VERSION 5.7 ;
  NOWIREEXTENSIONATPIN ON ;
  DIVIDERCHAR "/" ;
  BUSBITCHARS "[]" ;
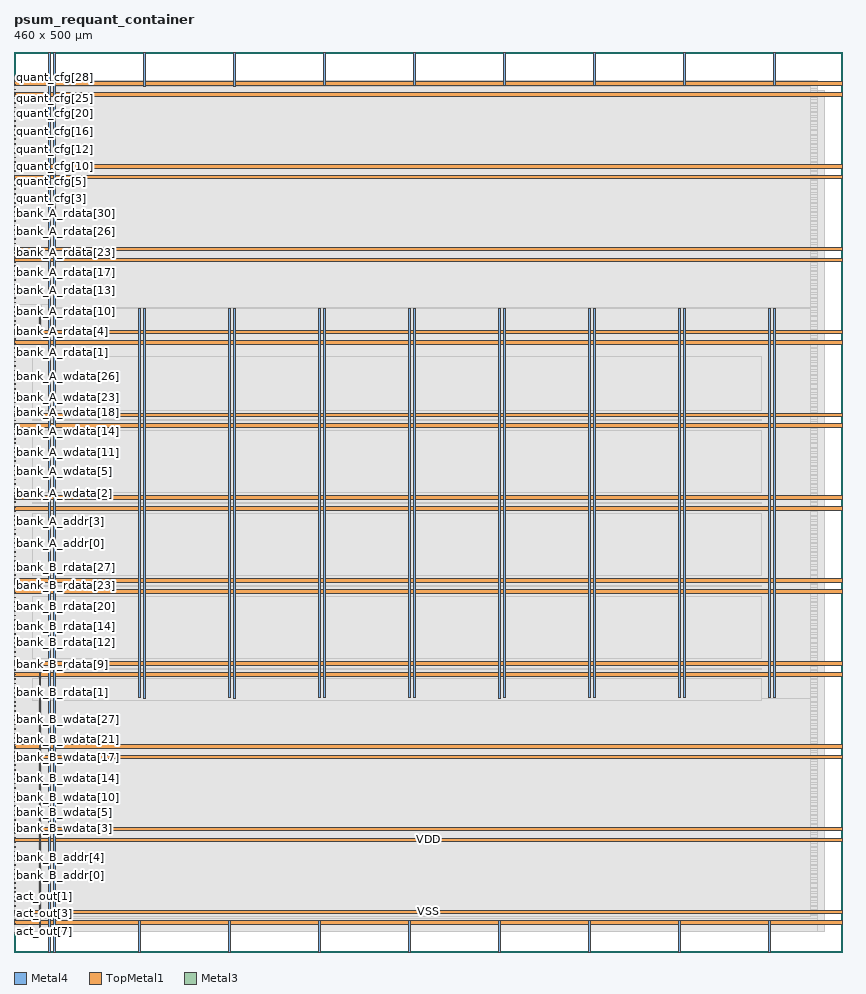
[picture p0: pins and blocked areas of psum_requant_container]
MACRO psum_requant_container
  CLASS BLOCK ;
  FOREIGN psum_requant_container ;
  ORIGIN 0.000 0.000 ;
  SIZE 460.000 BY 500.000 ;
  PIN VDD
    DIRECTION INOUT ;
    USE POWER ;
    PORT
      LAYER Metal4 ;
        RECT 19.100 0.000 20.100 500.000 ;
    END
    PORT
      LAYER Metal4 ;
        RECT 69.100 0.000 70.100 17.520 ;
    END
    PORT
      LAYER Metal4 ;
        RECT 69.100 141.260 70.100 357.520 ;
    END
    PORT
      LAYER Metal4 ;
        RECT 119.100 0.000 120.100 17.520 ;
    END
    PORT
      LAYER Metal4 ;
        RECT 119.100 141.260 120.100 357.520 ;
    END
    PORT
      LAYER Metal4 ;
        RECT 169.100 0.000 170.100 17.520 ;
    END
    PORT
      LAYER Metal4 ;
        RECT 169.100 141.260 170.100 357.520 ;
    END
    PORT
      LAYER Metal4 ;
        RECT 219.100 0.000 220.100 17.520 ;
    END
    PORT
      LAYER Metal4 ;
        RECT 219.100 141.260 220.100 357.520 ;
    END
    PORT
      LAYER Metal4 ;
        RECT 269.100 0.000 270.100 17.760 ;
    END
    PORT
      LAYER Metal4 ;
        RECT 269.100 141.020 270.100 357.760 ;
    END
    PORT
      LAYER Metal4 ;
        RECT 319.100 0.000 320.100 17.520 ;
    END
    PORT
      LAYER Metal4 ;
        RECT 319.100 141.260 320.100 357.520 ;
    END
    PORT
      LAYER Metal4 ;
        RECT 369.100 0.000 370.100 17.520 ;
    END
    PORT
      LAYER Metal4 ;
        RECT 369.100 141.260 370.100 357.520 ;
    END
    PORT
      LAYER Metal4 ;
        RECT 419.100 0.000 420.100 17.520 ;
    END
    PORT
      LAYER Metal4 ;
        RECT 419.100 141.260 420.100 357.520 ;
    END
    PORT
      LAYER TopMetal1 ;
        RECT 0.000 15.240 460.000 17.240 ;
    END
    PORT
      LAYER TopMetal1 ;
        RECT 0.000 61.270 460.000 63.270 ;
    END
    PORT
      LAYER TopMetal1 ;
        RECT 0.000 107.300 460.000 109.300 ;
    END
    PORT
      LAYER TopMetal1 ;
        RECT 0.000 153.330 460.000 155.330 ;
    END
    PORT
      LAYER TopMetal1 ;
        RECT 0.000 199.360 460.000 201.360 ;
    END
    PORT
      LAYER TopMetal1 ;
        RECT 0.000 245.390 460.000 247.390 ;
    END
    PORT
      LAYER TopMetal1 ;
        RECT 0.000 291.420 460.000 293.420 ;
    END
    PORT
      LAYER TopMetal1 ;
        RECT 0.000 337.450 460.000 339.450 ;
    END
    PORT
      LAYER TopMetal1 ;
        RECT 0.000 383.480 460.000 385.480 ;
    END
    PORT
      LAYER TopMetal1 ;
        RECT 0.000 429.510 460.000 431.510 ;
    END
    PORT
      LAYER TopMetal1 ;
        RECT 0.000 475.540 460.000 477.540 ;
    END
  END VDD
  PIN VSS
    DIRECTION INOUT ;
    USE GROUND ;
    PORT
      LAYER Metal4 ;
        RECT 22.100 0.000 23.100 500.000 ;
    END
    PORT
      LAYER Metal4 ;
        RECT 72.100 141.020 73.100 357.760 ;
    END
    PORT
      LAYER Metal4 ;
        RECT 72.100 481.020 73.100 500.000 ;
    END
    PORT
      LAYER Metal4 ;
        RECT 122.100 141.020 123.100 357.760 ;
    END
    PORT
      LAYER Metal4 ;
        RECT 122.100 481.020 123.100 500.000 ;
    END
    PORT
      LAYER Metal4 ;
        RECT 172.100 141.260 173.100 357.520 ;
    END
    PORT
      LAYER Metal4 ;
        RECT 172.100 481.260 173.100 500.000 ;
    END
    PORT
      LAYER Metal4 ;
        RECT 222.100 141.260 223.100 357.520 ;
    END
    PORT
      LAYER Metal4 ;
        RECT 222.100 481.260 223.100 500.000 ;
    END
    PORT
      LAYER Metal4 ;
        RECT 272.100 141.260 273.100 357.520 ;
    END
    PORT
      LAYER Metal4 ;
        RECT 272.100 481.260 273.100 500.000 ;
    END
    PORT
      LAYER Metal4 ;
        RECT 322.100 141.260 323.100 357.520 ;
    END
    PORT
      LAYER Metal4 ;
        RECT 322.100 481.260 323.100 500.000 ;
    END
    PORT
      LAYER Metal4 ;
        RECT 372.100 141.260 373.100 357.520 ;
    END
    PORT
      LAYER Metal4 ;
        RECT 372.100 481.260 373.100 500.000 ;
    END
    PORT
      LAYER Metal4 ;
        RECT 422.100 141.260 423.100 357.520 ;
    END
    PORT
      LAYER Metal4 ;
        RECT 422.100 481.260 423.100 500.000 ;
    END
    PORT
      LAYER TopMetal1 ;
        RECT 0.000 21.240 460.000 23.240 ;
    END
    PORT
      LAYER TopMetal1 ;
        RECT 0.000 67.270 460.000 69.270 ;
    END
    PORT
      LAYER TopMetal1 ;
        RECT 0.000 113.300 460.000 115.300 ;
    END
    PORT
      LAYER TopMetal1 ;
        RECT 0.000 159.330 460.000 161.330 ;
    END
    PORT
      LAYER TopMetal1 ;
        RECT 0.000 205.360 460.000 207.360 ;
    END
    PORT
      LAYER TopMetal1 ;
        RECT 0.000 251.390 460.000 253.390 ;
    END
    PORT
      LAYER TopMetal1 ;
        RECT 0.000 297.420 460.000 299.420 ;
    END
    PORT
      LAYER TopMetal1 ;
        RECT 0.000 343.450 460.000 345.450 ;
    END
    PORT
      LAYER TopMetal1 ;
        RECT 0.000 389.480 460.000 391.480 ;
    END
    PORT
      LAYER TopMetal1 ;
        RECT 0.000 435.510 460.000 437.510 ;
    END
    PORT
      LAYER TopMetal1 ;
        RECT 0.000 481.540 460.000 483.540 ;
    END
    PORT
      LAYER Metal4 ;
        RECT 13.900 11.120 14.900 155.200 ;
    END
    PORT
      LAYER Metal4 ;
        RECT 13.900 343.760 14.900 359.320 ;
    END
  END VSS
  PIN act_out[0]
    DIRECTION OUTPUT ;
    USE SIGNAL ;
    ANTENNADIFFAREA 0.708600 ;
    PORT
      LAYER Metal3 ;
        RECT 0.000 32.980 1.000 33.380 ;
    END
  END act_out[0]
  PIN act_out[1]
    DIRECTION OUTPUT ;
    USE SIGNAL ;
    ANTENNADIFFAREA 0.708600 ;
    PORT
      LAYER Metal3 ;
        RECT 0.000 30.460 1.000 30.860 ;
    END
  END act_out[1]
  PIN act_out[2]
    DIRECTION OUTPUT ;
    USE SIGNAL ;
    ANTENNADIFFAREA 0.708600 ;
    PORT
      LAYER Metal3 ;
        RECT 0.000 27.940 1.000 28.340 ;
    END
  END act_out[2]
  PIN act_out[3]
    DIRECTION OUTPUT ;
    USE SIGNAL ;
    ANTENNADIFFAREA 0.708600 ;
    PORT
      LAYER Metal3 ;
        RECT 0.000 25.420 1.000 25.820 ;
    END
  END act_out[3]
  PIN act_out[4]
    DIRECTION OUTPUT ;
    USE SIGNAL ;
    ANTENNADIFFAREA 0.708600 ;
    PORT
      LAYER Metal3 ;
        RECT 0.000 22.900 1.000 23.300 ;
    END
  END act_out[4]
  PIN act_out[5]
    DIRECTION OUTPUT ;
    USE SIGNAL ;
    ANTENNADIFFAREA 0.708600 ;
    PORT
      LAYER Metal3 ;
        RECT 0.000 20.380 1.000 20.780 ;
    END
  END act_out[5]
  PIN act_out[6]
    DIRECTION OUTPUT ;
    USE SIGNAL ;
    ANTENNADIFFAREA 0.708600 ;
    PORT
      LAYER Metal3 ;
        RECT 0.000 17.860 1.000 18.260 ;
    END
  END act_out[6]
  PIN act_out[7]
    DIRECTION OUTPUT ;
    USE SIGNAL ;
    ANTENNADIFFAREA 0.708600 ;
    PORT
      LAYER Metal3 ;
        RECT 0.000 15.340 1.000 15.740 ;
    END
  END act_out[7]
  PIN bank_A_addr[0]
    DIRECTION INPUT ;
    USE SIGNAL ;
    ANTENNAGATEAREA 0.180700 ;
    PORT
      LAYER Metal3 ;
        RECT 0.000 227.020 1.000 227.420 ;
    END
  END bank_A_addr[0]
  PIN bank_A_addr[1]
    DIRECTION INPUT ;
    USE SIGNAL ;
    ANTENNAGATEAREA 0.180700 ;
    PORT
      LAYER Metal3 ;
        RECT 0.000 229.540 1.000 229.940 ;
    END
  END bank_A_addr[1]
  PIN bank_A_addr[2]
    DIRECTION INPUT ;
    USE SIGNAL ;
    ANTENNAGATEAREA 0.180700 ;
    PORT
      LAYER Metal3 ;
        RECT 0.000 232.060 1.000 232.460 ;
    END
  END bank_A_addr[2]
  PIN bank_A_addr[3]
    DIRECTION INPUT ;
    USE SIGNAL ;
    ANTENNAGATEAREA 0.180700 ;
    PORT
      LAYER Metal3 ;
        RECT 0.000 234.580 1.000 234.980 ;
    END
  END bank_A_addr[3]
  PIN bank_A_addr[4]
    DIRECTION INPUT ;
    USE SIGNAL ;
    ANTENNAGATEAREA 0.180700 ;
    PORT
      LAYER Metal3 ;
        RECT 0.000 237.100 1.000 237.500 ;
    END
  END bank_A_addr[4]
  PIN bank_A_addr[5]
    DIRECTION INPUT ;
    USE SIGNAL ;
    ANTENNAGATEAREA 0.180700 ;
    PORT
      LAYER Metal3 ;
        RECT 0.000 239.620 1.000 240.020 ;
    END
  END bank_A_addr[5]
  PIN bank_A_addr[6]
    DIRECTION INPUT ;
    USE SIGNAL ;
    ANTENNAGATEAREA 0.180700 ;
    PORT
      LAYER Metal3 ;
        RECT 0.000 242.140 1.000 242.540 ;
    END
  END bank_A_addr[6]
  PIN bank_A_addr[7]
    DIRECTION INPUT ;
    USE SIGNAL ;
    ANTENNAGATEAREA 0.180700 ;
    PORT
      LAYER Metal3 ;
        RECT 0.000 244.660 1.000 245.060 ;
    END
  END bank_A_addr[7]
  PIN bank_A_rdata[0]
    DIRECTION OUTPUT ;
    USE SIGNAL ;
    ANTENNADIFFAREA 0.708600 ;
    PORT
      LAYER Metal3 ;
        RECT 0.000 330.340 1.000 330.740 ;
    END
  END bank_A_rdata[0]
  PIN bank_A_rdata[10]
    DIRECTION OUTPUT ;
    USE SIGNAL ;
    ANTENNADIFFAREA 0.708600 ;
    PORT
      LAYER Metal3 ;
        RECT 0.000 355.540 1.000 355.940 ;
    END
  END bank_A_rdata[10]
  PIN bank_A_rdata[11]
    DIRECTION OUTPUT ;
    USE SIGNAL ;
    ANTENNADIFFAREA 0.708600 ;
    PORT
      LAYER Metal3 ;
        RECT 0.000 358.060 1.000 358.460 ;
    END
  END bank_A_rdata[11]
  PIN bank_A_rdata[12]
    DIRECTION OUTPUT ;
    USE SIGNAL ;
    ANTENNADIFFAREA 0.708600 ;
    PORT
      LAYER Metal3 ;
        RECT 0.000 360.580 1.000 360.980 ;
    END
  END bank_A_rdata[12]
  PIN bank_A_rdata[13]
    DIRECTION OUTPUT ;
    USE SIGNAL ;
    ANTENNADIFFAREA 0.708600 ;
    PORT
      LAYER Metal3 ;
        RECT 0.000 363.100 1.000 363.500 ;
    END
  END bank_A_rdata[13]
  PIN bank_A_rdata[14]
    DIRECTION OUTPUT ;
    USE SIGNAL ;
    ANTENNADIFFAREA 0.708600 ;
    PORT
      LAYER Metal3 ;
        RECT 0.000 365.620 1.000 366.020 ;
    END
  END bank_A_rdata[14]
  PIN bank_A_rdata[15]
    DIRECTION OUTPUT ;
    USE SIGNAL ;
    ANTENNADIFFAREA 0.708600 ;
    PORT
      LAYER Metal3 ;
        RECT 0.000 368.140 1.000 368.540 ;
    END
  END bank_A_rdata[15]
  PIN bank_A_rdata[16]
    DIRECTION OUTPUT ;
    USE SIGNAL ;
    ANTENNADIFFAREA 0.708600 ;
    PORT
      LAYER Metal3 ;
        RECT 0.000 370.660 1.000 371.060 ;
    END
  END bank_A_rdata[16]
  PIN bank_A_rdata[17]
    DIRECTION OUTPUT ;
    USE SIGNAL ;
    ANTENNADIFFAREA 0.708600 ;
    PORT
      LAYER Metal3 ;
        RECT 0.000 373.180 1.000 373.580 ;
    END
  END bank_A_rdata[17]
  PIN bank_A_rdata[18]
    DIRECTION OUTPUT ;
    USE SIGNAL ;
    ANTENNADIFFAREA 0.708600 ;
    PORT
      LAYER Metal3 ;
        RECT 0.000 375.700 1.000 376.100 ;
    END
  END bank_A_rdata[18]
  PIN bank_A_rdata[19]
    DIRECTION OUTPUT ;
    USE SIGNAL ;
    ANTENNADIFFAREA 0.708600 ;
    PORT
      LAYER Metal3 ;
        RECT 0.000 378.220 1.000 378.620 ;
    END
  END bank_A_rdata[19]
  PIN bank_A_rdata[1]
    DIRECTION OUTPUT ;
    USE SIGNAL ;
    ANTENNADIFFAREA 0.708600 ;
    PORT
      LAYER Metal3 ;
        RECT 0.000 332.860 1.000 333.260 ;
    END
  END bank_A_rdata[1]
  PIN bank_A_rdata[20]
    DIRECTION OUTPUT ;
    USE SIGNAL ;
    ANTENNADIFFAREA 0.708600 ;
    PORT
      LAYER Metal3 ;
        RECT 0.000 380.740 1.000 381.140 ;
    END
  END bank_A_rdata[20]
  PIN bank_A_rdata[21]
    DIRECTION OUTPUT ;
    USE SIGNAL ;
    ANTENNADIFFAREA 0.708600 ;
    PORT
      LAYER Metal3 ;
        RECT 0.000 383.260 1.000 383.660 ;
    END
  END bank_A_rdata[21]
  PIN bank_A_rdata[22]
    DIRECTION OUTPUT ;
    USE SIGNAL ;
    ANTENNADIFFAREA 0.708600 ;
    PORT
      LAYER Metal3 ;
        RECT 0.000 385.780 1.000 386.180 ;
    END
  END bank_A_rdata[22]
  PIN bank_A_rdata[23]
    DIRECTION OUTPUT ;
    USE SIGNAL ;
    ANTENNADIFFAREA 0.708600 ;
    PORT
      LAYER Metal3 ;
        RECT 0.000 388.300 1.000 388.700 ;
    END
  END bank_A_rdata[23]
  PIN bank_A_rdata[24]
    DIRECTION OUTPUT ;
    USE SIGNAL ;
    ANTENNADIFFAREA 0.708600 ;
    PORT
      LAYER Metal3 ;
        RECT 0.000 390.820 1.000 391.220 ;
    END
  END bank_A_rdata[24]
  PIN bank_A_rdata[25]
    DIRECTION OUTPUT ;
    USE SIGNAL ;
    ANTENNADIFFAREA 0.708600 ;
    PORT
      LAYER Metal3 ;
        RECT 0.000 393.340 1.000 393.740 ;
    END
  END bank_A_rdata[25]
  PIN bank_A_rdata[26]
    DIRECTION OUTPUT ;
    USE SIGNAL ;
    ANTENNADIFFAREA 0.708600 ;
    PORT
      LAYER Metal3 ;
        RECT 0.000 395.860 1.000 396.260 ;
    END
  END bank_A_rdata[26]
  PIN bank_A_rdata[27]
    DIRECTION OUTPUT ;
    USE SIGNAL ;
    ANTENNADIFFAREA 0.708600 ;
    PORT
      LAYER Metal3 ;
        RECT 0.000 398.380 1.000 398.780 ;
    END
  END bank_A_rdata[27]
  PIN bank_A_rdata[28]
    DIRECTION OUTPUT ;
    USE SIGNAL ;
    ANTENNADIFFAREA 0.708600 ;
    PORT
      LAYER Metal3 ;
        RECT 0.000 400.900 1.000 401.300 ;
    END
  END bank_A_rdata[28]
  PIN bank_A_rdata[29]
    DIRECTION OUTPUT ;
    USE SIGNAL ;
    ANTENNADIFFAREA 0.708600 ;
    PORT
      LAYER Metal3 ;
        RECT 0.000 403.420 1.000 403.820 ;
    END
  END bank_A_rdata[29]
  PIN bank_A_rdata[2]
    DIRECTION OUTPUT ;
    USE SIGNAL ;
    ANTENNADIFFAREA 0.708600 ;
    PORT
      LAYER Metal3 ;
        RECT 0.000 335.380 1.000 335.780 ;
    END
  END bank_A_rdata[2]
  PIN bank_A_rdata[30]
    DIRECTION OUTPUT ;
    USE SIGNAL ;
    ANTENNADIFFAREA 0.708600 ;
    PORT
      LAYER Metal3 ;
        RECT 0.000 405.940 1.000 406.340 ;
    END
  END bank_A_rdata[30]
  PIN bank_A_rdata[31]
    DIRECTION OUTPUT ;
    USE SIGNAL ;
    ANTENNADIFFAREA 0.708600 ;
    PORT
      LAYER Metal3 ;
        RECT 0.000 408.460 1.000 408.860 ;
    END
  END bank_A_rdata[31]
  PIN bank_A_rdata[3]
    DIRECTION OUTPUT ;
    USE SIGNAL ;
    ANTENNADIFFAREA 0.708600 ;
    PORT
      LAYER Metal3 ;
        RECT 0.000 337.900 1.000 338.300 ;
    END
  END bank_A_rdata[3]
  PIN bank_A_rdata[4]
    DIRECTION OUTPUT ;
    USE SIGNAL ;
    ANTENNADIFFAREA 0.708600 ;
    PORT
      LAYER Metal3 ;
        RECT 0.000 340.420 1.000 340.820 ;
    END
  END bank_A_rdata[4]
  PIN bank_A_rdata[5]
    DIRECTION OUTPUT ;
    USE SIGNAL ;
    ANTENNADIFFAREA 0.708600 ;
    PORT
      LAYER Metal3 ;
        RECT 0.000 342.940 1.000 343.340 ;
    END
  END bank_A_rdata[5]
  PIN bank_A_rdata[6]
    DIRECTION OUTPUT ;
    USE SIGNAL ;
    ANTENNADIFFAREA 0.708600 ;
    PORT
      LAYER Metal3 ;
        RECT 0.000 345.460 1.000 345.860 ;
    END
  END bank_A_rdata[6]
  PIN bank_A_rdata[7]
    DIRECTION OUTPUT ;
    USE SIGNAL ;
    ANTENNADIFFAREA 0.708600 ;
    PORT
      LAYER Metal3 ;
        RECT 0.000 347.980 1.000 348.380 ;
    END
  END bank_A_rdata[7]
  PIN bank_A_rdata[8]
    DIRECTION OUTPUT ;
    USE SIGNAL ;
    ANTENNADIFFAREA 0.708600 ;
    PORT
      LAYER Metal3 ;
        RECT 0.000 350.500 1.000 350.900 ;
    END
  END bank_A_rdata[8]
  PIN bank_A_rdata[9]
    DIRECTION OUTPUT ;
    USE SIGNAL ;
    ANTENNADIFFAREA 0.708600 ;
    PORT
      LAYER Metal3 ;
        RECT 0.000 353.020 1.000 353.420 ;
    END
  END bank_A_rdata[9]
  PIN bank_A_wdata[0]
    DIRECTION INPUT ;
    USE SIGNAL ;
    ANTENNAGATEAREA 0.180700 ;
    PORT
      LAYER Metal3 ;
        RECT 0.000 249.700 1.000 250.100 ;
    END
  END bank_A_wdata[0]
  PIN bank_A_wdata[10]
    DIRECTION INPUT ;
    USE SIGNAL ;
    ANTENNAGATEAREA 0.180700 ;
    PORT
      LAYER Metal3 ;
        RECT 0.000 274.900 1.000 275.300 ;
    END
  END bank_A_wdata[10]
  PIN bank_A_wdata[11]
    DIRECTION INPUT ;
    USE SIGNAL ;
    ANTENNAGATEAREA 0.180700 ;
    PORT
      LAYER Metal3 ;
        RECT 0.000 277.420 1.000 277.820 ;
    END
  END bank_A_wdata[11]
  PIN bank_A_wdata[12]
    DIRECTION INPUT ;
    USE SIGNAL ;
    ANTENNAGATEAREA 0.180700 ;
    PORT
      LAYER Metal3 ;
        RECT 0.000 279.940 1.000 280.340 ;
    END
  END bank_A_wdata[12]
  PIN bank_A_wdata[13]
    DIRECTION INPUT ;
    USE SIGNAL ;
    ANTENNAGATEAREA 0.180700 ;
    PORT
      LAYER Metal3 ;
        RECT 0.000 282.460 1.000 282.860 ;
    END
  END bank_A_wdata[13]
  PIN bank_A_wdata[14]
    DIRECTION INPUT ;
    USE SIGNAL ;
    ANTENNAGATEAREA 0.180700 ;
    PORT
      LAYER Metal3 ;
        RECT 0.000 284.980 1.000 285.380 ;
    END
  END bank_A_wdata[14]
  PIN bank_A_wdata[15]
    DIRECTION INPUT ;
    USE SIGNAL ;
    ANTENNAGATEAREA 0.180700 ;
    PORT
      LAYER Metal3 ;
        RECT 0.000 287.500 1.000 287.900 ;
    END
  END bank_A_wdata[15]
  PIN bank_A_wdata[16]
    DIRECTION INPUT ;
    USE SIGNAL ;
    ANTENNAGATEAREA 0.180700 ;
    PORT
      LAYER Metal3 ;
        RECT 0.000 290.020 1.000 290.420 ;
    END
  END bank_A_wdata[16]
  PIN bank_A_wdata[17]
    DIRECTION INPUT ;
    USE SIGNAL ;
    ANTENNAGATEAREA 0.180700 ;
    PORT
      LAYER Metal3 ;
        RECT 0.000 292.540 1.000 292.940 ;
    END
  END bank_A_wdata[17]
  PIN bank_A_wdata[18]
    DIRECTION INPUT ;
    USE SIGNAL ;
    ANTENNAGATEAREA 0.180700 ;
    PORT
      LAYER Metal3 ;
        RECT 0.000 295.060 1.000 295.460 ;
    END
  END bank_A_wdata[18]
  PIN bank_A_wdata[19]
    DIRECTION INPUT ;
    USE SIGNAL ;
    ANTENNAGATEAREA 0.180700 ;
    PORT
      LAYER Metal3 ;
        RECT 0.000 297.580 1.000 297.980 ;
    END
  END bank_A_wdata[19]
  PIN bank_A_wdata[1]
    DIRECTION INPUT ;
    USE SIGNAL ;
    ANTENNAGATEAREA 0.180700 ;
    PORT
      LAYER Metal3 ;
        RECT 0.000 252.220 1.000 252.620 ;
    END
  END bank_A_wdata[1]
  PIN bank_A_wdata[20]
    DIRECTION INPUT ;
    USE SIGNAL ;
    ANTENNAGATEAREA 0.180700 ;
    PORT
      LAYER Metal3 ;
        RECT 0.000 300.100 1.000 300.500 ;
    END
  END bank_A_wdata[20]
  PIN bank_A_wdata[21]
    DIRECTION INPUT ;
    USE SIGNAL ;
    ANTENNAGATEAREA 0.180700 ;
    PORT
      LAYER Metal3 ;
        RECT 0.000 302.620 1.000 303.020 ;
    END
  END bank_A_wdata[21]
  PIN bank_A_wdata[22]
    DIRECTION INPUT ;
    USE SIGNAL ;
    ANTENNAGATEAREA 0.180700 ;
    PORT
      LAYER Metal3 ;
        RECT 0.000 305.140 1.000 305.540 ;
    END
  END bank_A_wdata[22]
  PIN bank_A_wdata[23]
    DIRECTION INPUT ;
    USE SIGNAL ;
    ANTENNAGATEAREA 0.180700 ;
    PORT
      LAYER Metal3 ;
        RECT 0.000 307.660 1.000 308.060 ;
    END
  END bank_A_wdata[23]
  PIN bank_A_wdata[24]
    DIRECTION INPUT ;
    USE SIGNAL ;
    ANTENNAGATEAREA 0.180700 ;
    PORT
      LAYER Metal3 ;
        RECT 0.000 310.180 1.000 310.580 ;
    END
  END bank_A_wdata[24]
  PIN bank_A_wdata[25]
    DIRECTION INPUT ;
    USE SIGNAL ;
    ANTENNAGATEAREA 0.180700 ;
    PORT
      LAYER Metal3 ;
        RECT 0.000 312.700 1.000 313.100 ;
    END
  END bank_A_wdata[25]
  PIN bank_A_wdata[26]
    DIRECTION INPUT ;
    USE SIGNAL ;
    ANTENNAGATEAREA 0.180700 ;
    PORT
      LAYER Metal3 ;
        RECT 0.000 315.220 1.000 315.620 ;
    END
  END bank_A_wdata[26]
  PIN bank_A_wdata[27]
    DIRECTION INPUT ;
    USE SIGNAL ;
    ANTENNAGATEAREA 0.180700 ;
    PORT
      LAYER Metal3 ;
        RECT 0.000 317.740 1.000 318.140 ;
    END
  END bank_A_wdata[27]
  PIN bank_A_wdata[28]
    DIRECTION INPUT ;
    USE SIGNAL ;
    ANTENNAGATEAREA 0.180700 ;
    PORT
      LAYER Metal3 ;
        RECT 0.000 320.260 1.000 320.660 ;
    END
  END bank_A_wdata[28]
  PIN bank_A_wdata[29]
    DIRECTION INPUT ;
    USE SIGNAL ;
    ANTENNAGATEAREA 0.180700 ;
    PORT
      LAYER Metal3 ;
        RECT 0.000 322.780 1.000 323.180 ;
    END
  END bank_A_wdata[29]
  PIN bank_A_wdata[2]
    DIRECTION INPUT ;
    USE SIGNAL ;
    ANTENNAGATEAREA 0.180700 ;
    PORT
      LAYER Metal3 ;
        RECT 0.000 254.740 1.000 255.140 ;
    END
  END bank_A_wdata[2]
  PIN bank_A_wdata[30]
    DIRECTION INPUT ;
    USE SIGNAL ;
    ANTENNAGATEAREA 0.180700 ;
    PORT
      LAYER Metal3 ;
        RECT 0.000 325.300 1.000 325.700 ;
    END
  END bank_A_wdata[30]
  PIN bank_A_wdata[31]
    DIRECTION INPUT ;
    USE SIGNAL ;
    ANTENNAGATEAREA 0.180700 ;
    PORT
      LAYER Metal3 ;
        RECT 0.000 327.820 1.000 328.220 ;
    END
  END bank_A_wdata[31]
  PIN bank_A_wdata[3]
    DIRECTION INPUT ;
    USE SIGNAL ;
    ANTENNAGATEAREA 0.180700 ;
    PORT
      LAYER Metal3 ;
        RECT 0.000 257.260 1.000 257.660 ;
    END
  END bank_A_wdata[3]
  PIN bank_A_wdata[4]
    DIRECTION INPUT ;
    USE SIGNAL ;
    ANTENNAGATEAREA 0.180700 ;
    PORT
      LAYER Metal3 ;
        RECT 0.000 259.780 1.000 260.180 ;
    END
  END bank_A_wdata[4]
  PIN bank_A_wdata[5]
    DIRECTION INPUT ;
    USE SIGNAL ;
    ANTENNAGATEAREA 0.180700 ;
    PORT
      LAYER Metal3 ;
        RECT 0.000 262.300 1.000 262.700 ;
    END
  END bank_A_wdata[5]
  PIN bank_A_wdata[6]
    DIRECTION INPUT ;
    USE SIGNAL ;
    ANTENNAGATEAREA 0.180700 ;
    PORT
      LAYER Metal3 ;
        RECT 0.000 264.820 1.000 265.220 ;
    END
  END bank_A_wdata[6]
  PIN bank_A_wdata[7]
    DIRECTION INPUT ;
    USE SIGNAL ;
    ANTENNAGATEAREA 0.180700 ;
    PORT
      LAYER Metal3 ;
        RECT 0.000 267.340 1.000 267.740 ;
    END
  END bank_A_wdata[7]
  PIN bank_A_wdata[8]
    DIRECTION INPUT ;
    USE SIGNAL ;
    ANTENNAGATEAREA 0.180700 ;
    PORT
      LAYER Metal3 ;
        RECT 0.000 269.860 1.000 270.260 ;
    END
  END bank_A_wdata[8]
  PIN bank_A_wdata[9]
    DIRECTION INPUT ;
    USE SIGNAL ;
    ANTENNAGATEAREA 0.180700 ;
    PORT
      LAYER Metal3 ;
        RECT 0.000 272.380 1.000 272.780 ;
    END
  END bank_A_wdata[9]
  PIN bank_A_we
    DIRECTION INPUT ;
    USE SIGNAL ;
    ANTENNAGATEAREA 0.180700 ;
    PORT
      LAYER Metal3 ;
        RECT 0.000 247.180 1.000 247.580 ;
    END
  END bank_A_we
  PIN bank_B_addr[0]
    DIRECTION INPUT ;
    USE SIGNAL ;
    ANTENNAGATEAREA 0.180700 ;
    PORT
      LAYER Metal3 ;
        RECT 0.000 38.020 1.000 38.420 ;
    END
  END bank_B_addr[0]
  PIN bank_B_addr[1]
    DIRECTION INPUT ;
    USE SIGNAL ;
    ANTENNAGATEAREA 0.180700 ;
    PORT
      LAYER Metal3 ;
        RECT 0.000 40.540 1.000 40.940 ;
    END
  END bank_B_addr[1]
  PIN bank_B_addr[2]
    DIRECTION INPUT ;
    USE SIGNAL ;
    ANTENNAGATEAREA 0.180700 ;
    PORT
      LAYER Metal3 ;
        RECT 0.000 43.060 1.000 43.460 ;
    END
  END bank_B_addr[2]
  PIN bank_B_addr[3]
    DIRECTION INPUT ;
    USE SIGNAL ;
    ANTENNAGATEAREA 0.180700 ;
    PORT
      LAYER Metal3 ;
        RECT 0.000 45.580 1.000 45.980 ;
    END
  END bank_B_addr[3]
  PIN bank_B_addr[4]
    DIRECTION INPUT ;
    USE SIGNAL ;
    ANTENNAGATEAREA 0.180700 ;
    PORT
      LAYER Metal3 ;
        RECT 0.000 48.100 1.000 48.500 ;
    END
  END bank_B_addr[4]
  PIN bank_B_addr[5]
    DIRECTION INPUT ;
    USE SIGNAL ;
    ANTENNAGATEAREA 0.180700 ;
    PORT
      LAYER Metal3 ;
        RECT 0.000 50.620 1.000 51.020 ;
    END
  END bank_B_addr[5]
  PIN bank_B_addr[6]
    DIRECTION INPUT ;
    USE SIGNAL ;
    ANTENNAGATEAREA 0.180700 ;
    PORT
      LAYER Metal3 ;
        RECT 0.000 53.140 1.000 53.540 ;
    END
  END bank_B_addr[6]
  PIN bank_B_addr[7]
    DIRECTION INPUT ;
    USE SIGNAL ;
    ANTENNAGATEAREA 0.180700 ;
    PORT
      LAYER Metal3 ;
        RECT 0.000 55.660 1.000 56.060 ;
    END
  END bank_B_addr[7]
  PIN bank_B_rdata[0]
    DIRECTION OUTPUT ;
    USE SIGNAL ;
    ANTENNADIFFAREA 0.708600 ;
    PORT
      LAYER Metal3 ;
        RECT 0.000 141.340 1.000 141.740 ;
    END
  END bank_B_rdata[0]
  PIN bank_B_rdata[10]
    DIRECTION OUTPUT ;
    USE SIGNAL ;
    ANTENNADIFFAREA 0.708600 ;
    PORT
      LAYER Metal3 ;
        RECT 0.000 166.540 1.000 166.940 ;
    END
  END bank_B_rdata[10]
  PIN bank_B_rdata[11]
    DIRECTION OUTPUT ;
    USE SIGNAL ;
    ANTENNADIFFAREA 0.708600 ;
    PORT
      LAYER Metal3 ;
        RECT 0.000 169.060 1.000 169.460 ;
    END
  END bank_B_rdata[11]
  PIN bank_B_rdata[12]
    DIRECTION OUTPUT ;
    USE SIGNAL ;
    ANTENNADIFFAREA 0.708600 ;
    PORT
      LAYER Metal3 ;
        RECT 0.000 171.580 1.000 171.980 ;
    END
  END bank_B_rdata[12]
  PIN bank_B_rdata[13]
    DIRECTION OUTPUT ;
    USE SIGNAL ;
    ANTENNADIFFAREA 0.708600 ;
    PORT
      LAYER Metal3 ;
        RECT 0.000 174.100 1.000 174.500 ;
    END
  END bank_B_rdata[13]
  PIN bank_B_rdata[14]
    DIRECTION OUTPUT ;
    USE SIGNAL ;
    ANTENNADIFFAREA 0.708600 ;
    PORT
      LAYER Metal3 ;
        RECT 0.000 176.620 1.000 177.020 ;
    END
  END bank_B_rdata[14]
  PIN bank_B_rdata[15]
    DIRECTION OUTPUT ;
    USE SIGNAL ;
    ANTENNADIFFAREA 0.708600 ;
    PORT
      LAYER Metal3 ;
        RECT 0.000 179.140 1.000 179.540 ;
    END
  END bank_B_rdata[15]
  PIN bank_B_rdata[16]
    DIRECTION OUTPUT ;
    USE SIGNAL ;
    ANTENNADIFFAREA 0.708600 ;
    PORT
      LAYER Metal3 ;
        RECT 0.000 181.660 1.000 182.060 ;
    END
  END bank_B_rdata[16]
  PIN bank_B_rdata[17]
    DIRECTION OUTPUT ;
    USE SIGNAL ;
    ANTENNADIFFAREA 0.708600 ;
    PORT
      LAYER Metal3 ;
        RECT 0.000 184.180 1.000 184.580 ;
    END
  END bank_B_rdata[17]
  PIN bank_B_rdata[18]
    DIRECTION OUTPUT ;
    USE SIGNAL ;
    ANTENNADIFFAREA 0.708600 ;
    PORT
      LAYER Metal3 ;
        RECT 0.000 186.700 1.000 187.100 ;
    END
  END bank_B_rdata[18]
  PIN bank_B_rdata[19]
    DIRECTION OUTPUT ;
    USE SIGNAL ;
    ANTENNADIFFAREA 0.708600 ;
    PORT
      LAYER Metal3 ;
        RECT 0.000 189.220 1.000 189.620 ;
    END
  END bank_B_rdata[19]
  PIN bank_B_rdata[1]
    DIRECTION OUTPUT ;
    USE SIGNAL ;
    ANTENNADIFFAREA 0.708600 ;
    PORT
      LAYER Metal3 ;
        RECT 0.000 143.860 1.000 144.260 ;
    END
  END bank_B_rdata[1]
  PIN bank_B_rdata[20]
    DIRECTION OUTPUT ;
    USE SIGNAL ;
    ANTENNADIFFAREA 0.708600 ;
    PORT
      LAYER Metal3 ;
        RECT 0.000 191.740 1.000 192.140 ;
    END
  END bank_B_rdata[20]
  PIN bank_B_rdata[21]
    DIRECTION OUTPUT ;
    USE SIGNAL ;
    ANTENNADIFFAREA 0.708600 ;
    PORT
      LAYER Metal3 ;
        RECT 0.000 194.260 1.000 194.660 ;
    END
  END bank_B_rdata[21]
  PIN bank_B_rdata[22]
    DIRECTION OUTPUT ;
    USE SIGNAL ;
    ANTENNADIFFAREA 0.708600 ;
    PORT
      LAYER Metal3 ;
        RECT 0.000 196.780 1.000 197.180 ;
    END
  END bank_B_rdata[22]
  PIN bank_B_rdata[23]
    DIRECTION OUTPUT ;
    USE SIGNAL ;
    ANTENNADIFFAREA 0.708600 ;
    PORT
      LAYER Metal3 ;
        RECT 0.000 199.300 1.000 199.700 ;
    END
  END bank_B_rdata[23]
  PIN bank_B_rdata[24]
    DIRECTION OUTPUT ;
    USE SIGNAL ;
    ANTENNADIFFAREA 0.708600 ;
    PORT
      LAYER Metal3 ;
        RECT 0.000 201.820 1.000 202.220 ;
    END
  END bank_B_rdata[24]
  PIN bank_B_rdata[25]
    DIRECTION OUTPUT ;
    USE SIGNAL ;
    ANTENNADIFFAREA 0.708600 ;
    PORT
      LAYER Metal3 ;
        RECT 0.000 204.340 1.000 204.740 ;
    END
  END bank_B_rdata[25]
  PIN bank_B_rdata[26]
    DIRECTION OUTPUT ;
    USE SIGNAL ;
    ANTENNADIFFAREA 0.708600 ;
    PORT
      LAYER Metal3 ;
        RECT 0.000 206.860 1.000 207.260 ;
    END
  END bank_B_rdata[26]
  PIN bank_B_rdata[27]
    DIRECTION OUTPUT ;
    USE SIGNAL ;
    ANTENNADIFFAREA 0.708600 ;
    PORT
      LAYER Metal3 ;
        RECT 0.000 209.380 1.000 209.780 ;
    END
  END bank_B_rdata[27]
  PIN bank_B_rdata[28]
    DIRECTION OUTPUT ;
    USE SIGNAL ;
    ANTENNADIFFAREA 0.708600 ;
    PORT
      LAYER Metal3 ;
        RECT 0.000 211.900 1.000 212.300 ;
    END
  END bank_B_rdata[28]
  PIN bank_B_rdata[29]
    DIRECTION OUTPUT ;
    USE SIGNAL ;
    ANTENNADIFFAREA 0.708600 ;
    PORT
      LAYER Metal3 ;
        RECT 0.000 214.420 1.000 214.820 ;
    END
  END bank_B_rdata[29]
  PIN bank_B_rdata[2]
    DIRECTION OUTPUT ;
    USE SIGNAL ;
    ANTENNADIFFAREA 0.708600 ;
    PORT
      LAYER Metal3 ;
        RECT 0.000 146.380 1.000 146.780 ;
    END
  END bank_B_rdata[2]
  PIN bank_B_rdata[30]
    DIRECTION OUTPUT ;
    USE SIGNAL ;
    ANTENNADIFFAREA 0.708600 ;
    PORT
      LAYER Metal3 ;
        RECT 0.000 216.940 1.000 217.340 ;
    END
  END bank_B_rdata[30]
  PIN bank_B_rdata[31]
    DIRECTION OUTPUT ;
    USE SIGNAL ;
    ANTENNADIFFAREA 0.708600 ;
    PORT
      LAYER Metal3 ;
        RECT 0.000 219.460 1.000 219.860 ;
    END
  END bank_B_rdata[31]
  PIN bank_B_rdata[3]
    DIRECTION OUTPUT ;
    USE SIGNAL ;
    ANTENNADIFFAREA 0.708600 ;
    PORT
      LAYER Metal3 ;
        RECT 0.000 148.900 1.000 149.300 ;
    END
  END bank_B_rdata[3]
  PIN bank_B_rdata[4]
    DIRECTION OUTPUT ;
    USE SIGNAL ;
    ANTENNADIFFAREA 0.708600 ;
    PORT
      LAYER Metal3 ;
        RECT 0.000 151.420 1.000 151.820 ;
    END
  END bank_B_rdata[4]
  PIN bank_B_rdata[5]
    DIRECTION OUTPUT ;
    USE SIGNAL ;
    ANTENNADIFFAREA 0.708600 ;
    PORT
      LAYER Metal3 ;
        RECT 0.000 153.940 1.000 154.340 ;
    END
  END bank_B_rdata[5]
  PIN bank_B_rdata[6]
    DIRECTION OUTPUT ;
    USE SIGNAL ;
    ANTENNADIFFAREA 0.708600 ;
    PORT
      LAYER Metal3 ;
        RECT 0.000 156.460 1.000 156.860 ;
    END
  END bank_B_rdata[6]
  PIN bank_B_rdata[7]
    DIRECTION OUTPUT ;
    USE SIGNAL ;
    ANTENNADIFFAREA 0.708600 ;
    PORT
      LAYER Metal3 ;
        RECT 0.000 158.980 1.000 159.380 ;
    END
  END bank_B_rdata[7]
  PIN bank_B_rdata[8]
    DIRECTION OUTPUT ;
    USE SIGNAL ;
    ANTENNADIFFAREA 0.708600 ;
    PORT
      LAYER Metal3 ;
        RECT 0.000 161.500 1.000 161.900 ;
    END
  END bank_B_rdata[8]
  PIN bank_B_rdata[9]
    DIRECTION OUTPUT ;
    USE SIGNAL ;
    ANTENNADIFFAREA 0.708600 ;
    PORT
      LAYER Metal3 ;
        RECT 0.000 164.020 1.000 164.420 ;
    END
  END bank_B_rdata[9]
  PIN bank_B_wdata[0]
    DIRECTION INPUT ;
    USE SIGNAL ;
    ANTENNAGATEAREA 0.180700 ;
    PORT
      LAYER Metal3 ;
        RECT 0.000 60.700 1.000 61.100 ;
    END
  END bank_B_wdata[0]
  PIN bank_B_wdata[10]
    DIRECTION INPUT ;
    USE SIGNAL ;
    ANTENNAGATEAREA 0.180700 ;
    PORT
      LAYER Metal3 ;
        RECT 0.000 85.900 1.000 86.300 ;
    END
  END bank_B_wdata[10]
  PIN bank_B_wdata[11]
    DIRECTION INPUT ;
    USE SIGNAL ;
    ANTENNAGATEAREA 0.180700 ;
    PORT
      LAYER Metal3 ;
        RECT 0.000 88.420 1.000 88.820 ;
    END
  END bank_B_wdata[11]
  PIN bank_B_wdata[12]
    DIRECTION INPUT ;
    USE SIGNAL ;
    ANTENNAGATEAREA 0.180700 ;
    PORT
      LAYER Metal3 ;
        RECT 0.000 90.940 1.000 91.340 ;
    END
  END bank_B_wdata[12]
  PIN bank_B_wdata[13]
    DIRECTION INPUT ;
    USE SIGNAL ;
    ANTENNAGATEAREA 0.180700 ;
    PORT
      LAYER Metal3 ;
        RECT 0.000 93.460 1.000 93.860 ;
    END
  END bank_B_wdata[13]
  PIN bank_B_wdata[14]
    DIRECTION INPUT ;
    USE SIGNAL ;
    ANTENNAGATEAREA 0.180700 ;
    PORT
      LAYER Metal3 ;
        RECT 0.000 95.980 1.000 96.380 ;
    END
  END bank_B_wdata[14]
  PIN bank_B_wdata[15]
    DIRECTION INPUT ;
    USE SIGNAL ;
    ANTENNAGATEAREA 0.180700 ;
    PORT
      LAYER Metal3 ;
        RECT 0.000 98.500 1.000 98.900 ;
    END
  END bank_B_wdata[15]
  PIN bank_B_wdata[16]
    DIRECTION INPUT ;
    USE SIGNAL ;
    ANTENNAGATEAREA 0.180700 ;
    PORT
      LAYER Metal3 ;
        RECT 0.000 101.020 1.000 101.420 ;
    END
  END bank_B_wdata[16]
  PIN bank_B_wdata[17]
    DIRECTION INPUT ;
    USE SIGNAL ;
    ANTENNAGATEAREA 0.180700 ;
    PORT
      LAYER Metal3 ;
        RECT 0.000 103.540 1.000 103.940 ;
    END
  END bank_B_wdata[17]
  PIN bank_B_wdata[18]
    DIRECTION INPUT ;
    USE SIGNAL ;
    ANTENNAGATEAREA 0.180700 ;
    PORT
      LAYER Metal3 ;
        RECT 0.000 106.060 1.000 106.460 ;
    END
  END bank_B_wdata[18]
  PIN bank_B_wdata[19]
    DIRECTION INPUT ;
    USE SIGNAL ;
    ANTENNAGATEAREA 0.180700 ;
    PORT
      LAYER Metal3 ;
        RECT 0.000 108.580 1.000 108.980 ;
    END
  END bank_B_wdata[19]
  PIN bank_B_wdata[1]
    DIRECTION INPUT ;
    USE SIGNAL ;
    ANTENNAGATEAREA 0.180700 ;
    PORT
      LAYER Metal3 ;
        RECT 0.000 63.220 1.000 63.620 ;
    END
  END bank_B_wdata[1]
  PIN bank_B_wdata[20]
    DIRECTION INPUT ;
    USE SIGNAL ;
    ANTENNAGATEAREA 0.180700 ;
    PORT
      LAYER Metal3 ;
        RECT 0.000 111.100 1.000 111.500 ;
    END
  END bank_B_wdata[20]
  PIN bank_B_wdata[21]
    DIRECTION INPUT ;
    USE SIGNAL ;
    ANTENNAGATEAREA 0.180700 ;
    PORT
      LAYER Metal3 ;
        RECT 0.000 113.620 1.000 114.020 ;
    END
  END bank_B_wdata[21]
  PIN bank_B_wdata[22]
    DIRECTION INPUT ;
    USE SIGNAL ;
    ANTENNAGATEAREA 0.180700 ;
    PORT
      LAYER Metal3 ;
        RECT 0.000 116.140 1.000 116.540 ;
    END
  END bank_B_wdata[22]
  PIN bank_B_wdata[23]
    DIRECTION INPUT ;
    USE SIGNAL ;
    ANTENNAGATEAREA 0.180700 ;
    PORT
      LAYER Metal3 ;
        RECT 0.000 118.660 1.000 119.060 ;
    END
  END bank_B_wdata[23]
  PIN bank_B_wdata[24]
    DIRECTION INPUT ;
    USE SIGNAL ;
    ANTENNAGATEAREA 0.180700 ;
    PORT
      LAYER Metal3 ;
        RECT 0.000 121.180 1.000 121.580 ;
    END
  END bank_B_wdata[24]
  PIN bank_B_wdata[25]
    DIRECTION INPUT ;
    USE SIGNAL ;
    ANTENNAGATEAREA 0.180700 ;
    PORT
      LAYER Metal3 ;
        RECT 0.000 123.700 1.000 124.100 ;
    END
  END bank_B_wdata[25]
  PIN bank_B_wdata[26]
    DIRECTION INPUT ;
    USE SIGNAL ;
    ANTENNAGATEAREA 0.180700 ;
    PORT
      LAYER Metal3 ;
        RECT 0.000 126.220 1.000 126.620 ;
    END
  END bank_B_wdata[26]
  PIN bank_B_wdata[27]
    DIRECTION INPUT ;
    USE SIGNAL ;
    ANTENNAGATEAREA 0.180700 ;
    PORT
      LAYER Metal3 ;
        RECT 0.000 128.740 1.000 129.140 ;
    END
  END bank_B_wdata[27]
  PIN bank_B_wdata[28]
    DIRECTION INPUT ;
    USE SIGNAL ;
    ANTENNAGATEAREA 0.180700 ;
    PORT
      LAYER Metal3 ;
        RECT 0.000 131.260 1.000 131.660 ;
    END
  END bank_B_wdata[28]
  PIN bank_B_wdata[29]
    DIRECTION INPUT ;
    USE SIGNAL ;
    ANTENNAGATEAREA 0.180700 ;
    PORT
      LAYER Metal3 ;
        RECT 0.000 133.780 1.000 134.180 ;
    END
  END bank_B_wdata[29]
  PIN bank_B_wdata[2]
    DIRECTION INPUT ;
    USE SIGNAL ;
    ANTENNAGATEAREA 0.180700 ;
    PORT
      LAYER Metal3 ;
        RECT 0.000 65.740 1.000 66.140 ;
    END
  END bank_B_wdata[2]
  PIN bank_B_wdata[30]
    DIRECTION INPUT ;
    USE SIGNAL ;
    ANTENNAGATEAREA 0.180700 ;
    PORT
      LAYER Metal3 ;
        RECT 0.000 136.300 1.000 136.700 ;
    END
  END bank_B_wdata[30]
  PIN bank_B_wdata[31]
    DIRECTION INPUT ;
    USE SIGNAL ;
    ANTENNAGATEAREA 0.180700 ;
    PORT
      LAYER Metal3 ;
        RECT 0.000 138.820 1.000 139.220 ;
    END
  END bank_B_wdata[31]
  PIN bank_B_wdata[3]
    DIRECTION INPUT ;
    USE SIGNAL ;
    ANTENNAGATEAREA 0.180700 ;
    PORT
      LAYER Metal3 ;
        RECT 0.000 68.260 1.000 68.660 ;
    END
  END bank_B_wdata[3]
  PIN bank_B_wdata[4]
    DIRECTION INPUT ;
    USE SIGNAL ;
    ANTENNAGATEAREA 0.180700 ;
    PORT
      LAYER Metal3 ;
        RECT 0.000 70.780 1.000 71.180 ;
    END
  END bank_B_wdata[4]
  PIN bank_B_wdata[5]
    DIRECTION INPUT ;
    USE SIGNAL ;
    ANTENNAGATEAREA 0.180700 ;
    PORT
      LAYER Metal3 ;
        RECT 0.000 73.300 1.000 73.700 ;
    END
  END bank_B_wdata[5]
  PIN bank_B_wdata[6]
    DIRECTION INPUT ;
    USE SIGNAL ;
    ANTENNAGATEAREA 0.180700 ;
    PORT
      LAYER Metal3 ;
        RECT 0.000 75.820 1.000 76.220 ;
    END
  END bank_B_wdata[6]
  PIN bank_B_wdata[7]
    DIRECTION INPUT ;
    USE SIGNAL ;
    ANTENNAGATEAREA 0.180700 ;
    PORT
      LAYER Metal3 ;
        RECT 0.000 78.340 1.000 78.740 ;
    END
  END bank_B_wdata[7]
  PIN bank_B_wdata[8]
    DIRECTION INPUT ;
    USE SIGNAL ;
    ANTENNAGATEAREA 0.180700 ;
    PORT
      LAYER Metal3 ;
        RECT 0.000 80.860 1.000 81.260 ;
    END
  END bank_B_wdata[8]
  PIN bank_B_wdata[9]
    DIRECTION INPUT ;
    USE SIGNAL ;
    ANTENNAGATEAREA 0.180700 ;
    PORT
      LAYER Metal3 ;
        RECT 0.000 83.380 1.000 83.780 ;
    END
  END bank_B_wdata[9]
  PIN bank_B_we
    DIRECTION INPUT ;
    USE SIGNAL ;
    ANTENNAGATEAREA 0.180700 ;
    PORT
      LAYER Metal3 ;
        RECT 0.000 58.180 1.000 58.580 ;
    END
  END bank_B_we
  PIN clk_i
    DIRECTION INPUT ;
    USE SIGNAL ;
    ANTENNAGATEAREA 2.901600 ;
    PORT
      LAYER Metal3 ;
        RECT 0.000 221.980 1.000 222.380 ;
    END
  END clk_i
  PIN psum_lut_en
    DIRECTION INPUT ;
    USE SIGNAL ;
    ANTENNAGATEAREA 0.180700 ;
    PORT
      LAYER Metal3 ;
        RECT 0.000 35.500 1.000 35.900 ;
    END
  END psum_lut_en
  PIN quant_cfg[0]
    DIRECTION INPUT ;
    USE SIGNAL ;
    ANTENNAGATEAREA 0.180700 ;
    PORT
      LAYER Metal3 ;
        RECT 0.000 410.980 1.000 411.380 ;
    END
  END quant_cfg[0]
  PIN quant_cfg[10]
    DIRECTION INPUT ;
    USE SIGNAL ;
    ANTENNAGATEAREA 0.180700 ;
    PORT
      LAYER Metal3 ;
        RECT 0.000 436.180 1.000 436.580 ;
    END
  END quant_cfg[10]
  PIN quant_cfg[11]
    DIRECTION INPUT ;
    USE SIGNAL ;
    ANTENNAGATEAREA 0.180700 ;
    PORT
      LAYER Metal3 ;
        RECT 0.000 438.700 1.000 439.100 ;
    END
  END quant_cfg[11]
  PIN quant_cfg[12]
    DIRECTION INPUT ;
    USE SIGNAL ;
    ANTENNAGATEAREA 0.180700 ;
    PORT
      LAYER Metal3 ;
        RECT 0.000 441.220 1.000 441.620 ;
    END
  END quant_cfg[12]
  PIN quant_cfg[13]
    DIRECTION INPUT ;
    USE SIGNAL ;
    ANTENNAGATEAREA 0.180700 ;
    PORT
      LAYER Metal3 ;
        RECT 0.000 443.740 1.000 444.140 ;
    END
  END quant_cfg[13]
  PIN quant_cfg[14]
    DIRECTION INPUT ;
    USE SIGNAL ;
    ANTENNAGATEAREA 0.180700 ;
    PORT
      LAYER Metal3 ;
        RECT 0.000 446.260 1.000 446.660 ;
    END
  END quant_cfg[14]
  PIN quant_cfg[15]
    DIRECTION INPUT ;
    USE SIGNAL ;
    ANTENNAGATEAREA 0.180700 ;
    PORT
      LAYER Metal3 ;
        RECT 0.000 448.780 1.000 449.180 ;
    END
  END quant_cfg[15]
  PIN quant_cfg[16]
    DIRECTION INPUT ;
    USE SIGNAL ;
    ANTENNAGATEAREA 0.180700 ;
    PORT
      LAYER Metal3 ;
        RECT 0.000 451.300 1.000 451.700 ;
    END
  END quant_cfg[16]
  PIN quant_cfg[17]
    DIRECTION INPUT ;
    USE SIGNAL ;
    ANTENNAGATEAREA 0.180700 ;
    PORT
      LAYER Metal3 ;
        RECT 0.000 453.820 1.000 454.220 ;
    END
  END quant_cfg[17]
  PIN quant_cfg[18]
    DIRECTION INPUT ;
    USE SIGNAL ;
    ANTENNAGATEAREA 0.180700 ;
    PORT
      LAYER Metal3 ;
        RECT 0.000 456.340 1.000 456.740 ;
    END
  END quant_cfg[18]
  PIN quant_cfg[19]
    DIRECTION INPUT ;
    USE SIGNAL ;
    ANTENNAGATEAREA 0.180700 ;
    PORT
      LAYER Metal3 ;
        RECT 0.000 458.860 1.000 459.260 ;
    END
  END quant_cfg[19]
  PIN quant_cfg[1]
    DIRECTION INPUT ;
    USE SIGNAL ;
    ANTENNAGATEAREA 0.180700 ;
    PORT
      LAYER Metal3 ;
        RECT 0.000 413.500 1.000 413.900 ;
    END
  END quant_cfg[1]
  PIN quant_cfg[20]
    DIRECTION INPUT ;
    USE SIGNAL ;
    ANTENNAGATEAREA 0.180700 ;
    PORT
      LAYER Metal3 ;
        RECT 0.000 461.380 1.000 461.780 ;
    END
  END quant_cfg[20]
  PIN quant_cfg[21]
    DIRECTION INPUT ;
    USE SIGNAL ;
    ANTENNAGATEAREA 0.180700 ;
    PORT
      LAYER Metal3 ;
        RECT 0.000 463.900 1.000 464.300 ;
    END
  END quant_cfg[21]
  PIN quant_cfg[22]
    DIRECTION INPUT ;
    USE SIGNAL ;
    ANTENNAGATEAREA 0.180700 ;
    PORT
      LAYER Metal3 ;
        RECT 0.000 466.420 1.000 466.820 ;
    END
  END quant_cfg[22]
  PIN quant_cfg[23]
    DIRECTION INPUT ;
    USE SIGNAL ;
    ANTENNAGATEAREA 0.180700 ;
    PORT
      LAYER Metal3 ;
        RECT 0.000 468.940 1.000 469.340 ;
    END
  END quant_cfg[23]
  PIN quant_cfg[24]
    DIRECTION INPUT ;
    USE SIGNAL ;
    ANTENNAGATEAREA 0.180700 ;
    PORT
      LAYER Metal3 ;
        RECT 0.000 471.460 1.000 471.860 ;
    END
  END quant_cfg[24]
  PIN quant_cfg[25]
    DIRECTION INPUT ;
    USE SIGNAL ;
    ANTENNAGATEAREA 0.180700 ;
    PORT
      LAYER Metal3 ;
        RECT 0.000 473.980 1.000 474.380 ;
    END
  END quant_cfg[25]
  PIN quant_cfg[26]
    DIRECTION INPUT ;
    USE SIGNAL ;
    ANTENNAGATEAREA 0.180700 ;
    PORT
      LAYER Metal3 ;
        RECT 0.000 476.500 1.000 476.900 ;
    END
  END quant_cfg[26]
  PIN quant_cfg[27]
    DIRECTION INPUT ;
    USE SIGNAL ;
    ANTENNAGATEAREA 0.180700 ;
    ANTENNADIFFAREA 2.015400 ;
    PORT
      LAYER Metal3 ;
        RECT 0.000 479.020 1.000 479.420 ;
    END
  END quant_cfg[27]
  PIN quant_cfg[28]
    DIRECTION INPUT ;
    USE SIGNAL ;
    ANTENNAGATEAREA 0.180700 ;
    PORT
      LAYER Metal3 ;
        RECT 0.000 481.540 1.000 481.940 ;
    END
  END quant_cfg[28]
  PIN quant_cfg[29]
    DIRECTION INPUT ;
    USE SIGNAL ;
    ANTENNAGATEAREA 0.180700 ;
    ANTENNADIFFAREA 2.015400 ;
    PORT
      LAYER Metal3 ;
        RECT 0.000 484.060 1.000 484.460 ;
    END
  END quant_cfg[29]
  PIN quant_cfg[2]
    DIRECTION INPUT ;
    USE SIGNAL ;
    ANTENNAGATEAREA 0.180700 ;
    PORT
      LAYER Metal3 ;
        RECT 0.000 416.020 1.000 416.420 ;
    END
  END quant_cfg[2]
  PIN quant_cfg[3]
    DIRECTION INPUT ;
    USE SIGNAL ;
    ANTENNAGATEAREA 0.180700 ;
    PORT
      LAYER Metal3 ;
        RECT 0.000 418.540 1.000 418.940 ;
    END
  END quant_cfg[3]
  PIN quant_cfg[4]
    DIRECTION INPUT ;
    USE SIGNAL ;
    ANTENNAGATEAREA 0.180700 ;
    PORT
      LAYER Metal3 ;
        RECT 0.000 421.060 1.000 421.460 ;
    END
  END quant_cfg[4]
  PIN quant_cfg[5]
    DIRECTION INPUT ;
    USE SIGNAL ;
    ANTENNAGATEAREA 0.180700 ;
    PORT
      LAYER Metal3 ;
        RECT 0.000 423.580 1.000 423.980 ;
    END
  END quant_cfg[5]
  PIN quant_cfg[6]
    DIRECTION INPUT ;
    USE SIGNAL ;
    ANTENNAGATEAREA 0.180700 ;
    PORT
      LAYER Metal3 ;
        RECT 0.000 426.100 1.000 426.500 ;
    END
  END quant_cfg[6]
  PIN quant_cfg[7]
    DIRECTION INPUT ;
    USE SIGNAL ;
    ANTENNAGATEAREA 0.180700 ;
    PORT
      LAYER Metal3 ;
        RECT 0.000 428.620 1.000 429.020 ;
    END
  END quant_cfg[7]
  PIN quant_cfg[8]
    DIRECTION INPUT ;
    USE SIGNAL ;
    ANTENNAGATEAREA 0.180700 ;
    PORT
      LAYER Metal3 ;
        RECT 0.000 431.140 1.000 431.540 ;
    END
  END quant_cfg[8]
  PIN quant_cfg[9]
    DIRECTION INPUT ;
    USE SIGNAL ;
    ANTENNAGATEAREA 0.180700 ;
    PORT
      LAYER Metal3 ;
        RECT 0.000 433.660 1.000 434.060 ;
    END
  END quant_cfg[9]
  PIN rst_n
    DIRECTION INPUT ;
    USE SIGNAL ;
    ANTENNAGATEAREA 0.361400 ;
    PORT
      LAYER Metal3 ;
        RECT 0.000 224.500 1.000 224.900 ;
    END
  END rst_n
  OBS
      LAYER GatPoly ;
        RECT 9.600 11.190 450.240 478.540 ;
      LAYER Metal1 ;
        RECT 9.600 11.120 450.240 478.495 ;
      LAYER Metal2 ;
        RECT 0.855 11.195 446.535 484.405 ;
      LAYER Metal3 ;
        RECT 1.210 483.850 446.640 484.360 ;
        RECT 0.335 482.150 446.640 483.850 ;
        RECT 1.210 481.330 446.640 482.150 ;
        RECT 0.335 479.630 446.640 481.330 ;
        RECT 1.210 478.810 446.640 479.630 ;
        RECT 0.335 477.110 446.640 478.810 ;
        RECT 1.210 476.290 446.640 477.110 ;
        RECT 0.335 474.590 446.640 476.290 ;
        RECT 1.210 473.770 446.640 474.590 ;
        RECT 0.335 472.070 446.640 473.770 ;
        RECT 1.210 471.250 446.640 472.070 ;
        RECT 0.335 469.550 446.640 471.250 ;
        RECT 1.210 468.730 446.640 469.550 ;
        RECT 0.335 467.030 446.640 468.730 ;
        RECT 1.210 466.210 446.640 467.030 ;
        RECT 0.335 464.510 446.640 466.210 ;
        RECT 1.210 463.690 446.640 464.510 ;
        RECT 0.335 461.990 446.640 463.690 ;
        RECT 1.210 461.170 446.640 461.990 ;
        RECT 0.335 459.470 446.640 461.170 ;
        RECT 1.210 458.650 446.640 459.470 ;
        RECT 0.335 456.950 446.640 458.650 ;
        RECT 1.210 456.130 446.640 456.950 ;
        RECT 0.335 454.430 446.640 456.130 ;
        RECT 1.210 453.610 446.640 454.430 ;
        RECT 0.335 451.910 446.640 453.610 ;
        RECT 1.210 451.090 446.640 451.910 ;
        RECT 0.335 449.390 446.640 451.090 ;
        RECT 1.210 448.570 446.640 449.390 ;
        RECT 0.335 446.870 446.640 448.570 ;
        RECT 1.210 446.050 446.640 446.870 ;
        RECT 0.335 444.350 446.640 446.050 ;
        RECT 1.210 443.530 446.640 444.350 ;
        RECT 0.335 441.830 446.640 443.530 ;
        RECT 1.210 441.010 446.640 441.830 ;
        RECT 0.335 439.310 446.640 441.010 ;
        RECT 1.210 438.490 446.640 439.310 ;
        RECT 0.335 436.790 446.640 438.490 ;
        RECT 1.210 435.970 446.640 436.790 ;
        RECT 0.335 434.270 446.640 435.970 ;
        RECT 1.210 433.450 446.640 434.270 ;
        RECT 0.335 431.750 446.640 433.450 ;
        RECT 1.210 430.930 446.640 431.750 ;
        RECT 0.335 429.230 446.640 430.930 ;
        RECT 1.210 428.410 446.640 429.230 ;
        RECT 0.335 426.710 446.640 428.410 ;
        RECT 1.210 425.890 446.640 426.710 ;
        RECT 0.335 424.190 446.640 425.890 ;
        RECT 1.210 423.370 446.640 424.190 ;
        RECT 0.335 421.670 446.640 423.370 ;
        RECT 1.210 420.850 446.640 421.670 ;
        RECT 0.335 419.150 446.640 420.850 ;
        RECT 1.210 418.330 446.640 419.150 ;
        RECT 0.335 416.630 446.640 418.330 ;
        RECT 1.210 415.810 446.640 416.630 ;
        RECT 0.335 414.110 446.640 415.810 ;
        RECT 1.210 413.290 446.640 414.110 ;
        RECT 0.335 411.590 446.640 413.290 ;
        RECT 1.210 410.770 446.640 411.590 ;
        RECT 0.335 409.070 446.640 410.770 ;
        RECT 1.210 408.250 446.640 409.070 ;
        RECT 0.335 406.550 446.640 408.250 ;
        RECT 1.210 405.730 446.640 406.550 ;
        RECT 0.335 404.030 446.640 405.730 ;
        RECT 1.210 403.210 446.640 404.030 ;
        RECT 0.335 401.510 446.640 403.210 ;
        RECT 1.210 400.690 446.640 401.510 ;
        RECT 0.335 398.990 446.640 400.690 ;
        RECT 1.210 398.170 446.640 398.990 ;
        RECT 0.335 396.470 446.640 398.170 ;
        RECT 1.210 395.650 446.640 396.470 ;
        RECT 0.335 393.950 446.640 395.650 ;
        RECT 1.210 393.130 446.640 393.950 ;
        RECT 0.335 391.430 446.640 393.130 ;
        RECT 1.210 390.610 446.640 391.430 ;
        RECT 0.335 388.910 446.640 390.610 ;
        RECT 1.210 388.090 446.640 388.910 ;
        RECT 0.335 386.390 446.640 388.090 ;
        RECT 1.210 385.570 446.640 386.390 ;
        RECT 0.335 383.870 446.640 385.570 ;
        RECT 1.210 383.050 446.640 383.870 ;
        RECT 0.335 381.350 446.640 383.050 ;
        RECT 1.210 380.530 446.640 381.350 ;
        RECT 0.335 378.830 446.640 380.530 ;
        RECT 1.210 378.010 446.640 378.830 ;
        RECT 0.335 376.310 446.640 378.010 ;
        RECT 1.210 375.490 446.640 376.310 ;
        RECT 0.335 373.790 446.640 375.490 ;
        RECT 1.210 372.970 446.640 373.790 ;
        RECT 0.335 371.270 446.640 372.970 ;
        RECT 1.210 370.450 446.640 371.270 ;
        RECT 0.335 368.750 446.640 370.450 ;
        RECT 1.210 367.930 446.640 368.750 ;
        RECT 0.335 366.230 446.640 367.930 ;
        RECT 1.210 365.410 446.640 366.230 ;
        RECT 0.335 363.710 446.640 365.410 ;
        RECT 1.210 362.890 446.640 363.710 ;
        RECT 0.335 361.190 446.640 362.890 ;
        RECT 1.210 360.370 446.640 361.190 ;
        RECT 0.335 358.670 446.640 360.370 ;
        RECT 1.210 357.850 446.640 358.670 ;
        RECT 0.335 356.150 446.640 357.850 ;
        RECT 1.210 355.330 446.640 356.150 ;
        RECT 0.335 353.630 446.640 355.330 ;
        RECT 1.210 352.810 446.640 353.630 ;
        RECT 0.335 351.110 446.640 352.810 ;
        RECT 1.210 350.290 446.640 351.110 ;
        RECT 0.335 348.590 446.640 350.290 ;
        RECT 1.210 347.770 446.640 348.590 ;
        RECT 0.335 346.070 446.640 347.770 ;
        RECT 1.210 345.250 446.640 346.070 ;
        RECT 0.335 343.550 446.640 345.250 ;
        RECT 1.210 342.730 446.640 343.550 ;
        RECT 0.335 341.030 446.640 342.730 ;
        RECT 1.210 340.210 446.640 341.030 ;
        RECT 0.335 338.510 446.640 340.210 ;
        RECT 1.210 337.690 446.640 338.510 ;
        RECT 0.335 335.990 446.640 337.690 ;
        RECT 1.210 335.170 446.640 335.990 ;
        RECT 0.335 333.470 446.640 335.170 ;
        RECT 1.210 332.650 446.640 333.470 ;
        RECT 0.335 330.950 446.640 332.650 ;
        RECT 1.210 330.130 446.640 330.950 ;
        RECT 0.335 328.430 446.640 330.130 ;
        RECT 1.210 327.610 446.640 328.430 ;
        RECT 0.335 325.910 446.640 327.610 ;
        RECT 1.210 325.090 446.640 325.910 ;
        RECT 0.335 323.390 446.640 325.090 ;
        RECT 1.210 322.570 446.640 323.390 ;
        RECT 0.335 320.870 446.640 322.570 ;
        RECT 1.210 320.050 446.640 320.870 ;
        RECT 0.335 318.350 446.640 320.050 ;
        RECT 1.210 317.530 446.640 318.350 ;
        RECT 0.335 315.830 446.640 317.530 ;
        RECT 1.210 315.010 446.640 315.830 ;
        RECT 0.335 313.310 446.640 315.010 ;
        RECT 1.210 312.490 446.640 313.310 ;
        RECT 0.335 310.790 446.640 312.490 ;
        RECT 1.210 309.970 446.640 310.790 ;
        RECT 0.335 308.270 446.640 309.970 ;
        RECT 1.210 307.450 446.640 308.270 ;
        RECT 0.335 305.750 446.640 307.450 ;
        RECT 1.210 304.930 446.640 305.750 ;
        RECT 0.335 303.230 446.640 304.930 ;
        RECT 1.210 302.410 446.640 303.230 ;
        RECT 0.335 300.710 446.640 302.410 ;
        RECT 1.210 299.890 446.640 300.710 ;
        RECT 0.335 298.190 446.640 299.890 ;
        RECT 1.210 297.370 446.640 298.190 ;
        RECT 0.335 295.670 446.640 297.370 ;
        RECT 1.210 294.850 446.640 295.670 ;
        RECT 0.335 293.150 446.640 294.850 ;
        RECT 1.210 292.330 446.640 293.150 ;
        RECT 0.335 290.630 446.640 292.330 ;
        RECT 1.210 289.810 446.640 290.630 ;
        RECT 0.335 288.110 446.640 289.810 ;
        RECT 1.210 287.290 446.640 288.110 ;
        RECT 0.335 285.590 446.640 287.290 ;
        RECT 1.210 284.770 446.640 285.590 ;
        RECT 0.335 283.070 446.640 284.770 ;
        RECT 1.210 282.250 446.640 283.070 ;
        RECT 0.335 280.550 446.640 282.250 ;
        RECT 1.210 279.730 446.640 280.550 ;
        RECT 0.335 278.030 446.640 279.730 ;
        RECT 1.210 277.210 446.640 278.030 ;
        RECT 0.335 275.510 446.640 277.210 ;
        RECT 1.210 274.690 446.640 275.510 ;
        RECT 0.335 272.990 446.640 274.690 ;
        RECT 1.210 272.170 446.640 272.990 ;
        RECT 0.335 270.470 446.640 272.170 ;
        RECT 1.210 269.650 446.640 270.470 ;
        RECT 0.335 267.950 446.640 269.650 ;
        RECT 1.210 267.130 446.640 267.950 ;
        RECT 0.335 265.430 446.640 267.130 ;
        RECT 1.210 264.610 446.640 265.430 ;
        RECT 0.335 262.910 446.640 264.610 ;
        RECT 1.210 262.090 446.640 262.910 ;
        RECT 0.335 260.390 446.640 262.090 ;
        RECT 1.210 259.570 446.640 260.390 ;
        RECT 0.335 257.870 446.640 259.570 ;
        RECT 1.210 257.050 446.640 257.870 ;
        RECT 0.335 255.350 446.640 257.050 ;
        RECT 1.210 254.530 446.640 255.350 ;
        RECT 0.335 252.830 446.640 254.530 ;
        RECT 1.210 252.010 446.640 252.830 ;
        RECT 0.335 250.310 446.640 252.010 ;
        RECT 1.210 249.490 446.640 250.310 ;
        RECT 0.335 247.790 446.640 249.490 ;
        RECT 1.210 246.970 446.640 247.790 ;
        RECT 0.335 245.270 446.640 246.970 ;
        RECT 1.210 244.450 446.640 245.270 ;
        RECT 0.335 242.750 446.640 244.450 ;
        RECT 1.210 241.930 446.640 242.750 ;
        RECT 0.335 240.230 446.640 241.930 ;
        RECT 1.210 239.410 446.640 240.230 ;
        RECT 0.335 237.710 446.640 239.410 ;
        RECT 1.210 236.890 446.640 237.710 ;
        RECT 0.335 235.190 446.640 236.890 ;
        RECT 1.210 234.370 446.640 235.190 ;
        RECT 0.335 232.670 446.640 234.370 ;
        RECT 1.210 231.850 446.640 232.670 ;
        RECT 0.335 230.150 446.640 231.850 ;
        RECT 1.210 229.330 446.640 230.150 ;
        RECT 0.335 227.630 446.640 229.330 ;
        RECT 1.210 226.810 446.640 227.630 ;
        RECT 0.335 225.110 446.640 226.810 ;
        RECT 1.210 224.290 446.640 225.110 ;
        RECT 0.335 222.590 446.640 224.290 ;
        RECT 1.210 221.770 446.640 222.590 ;
        RECT 0.335 220.070 446.640 221.770 ;
        RECT 1.210 219.250 446.640 220.070 ;
        RECT 0.335 217.550 446.640 219.250 ;
        RECT 1.210 216.730 446.640 217.550 ;
        RECT 0.335 215.030 446.640 216.730 ;
        RECT 1.210 214.210 446.640 215.030 ;
        RECT 0.335 212.510 446.640 214.210 ;
        RECT 1.210 211.690 446.640 212.510 ;
        RECT 0.335 209.990 446.640 211.690 ;
        RECT 1.210 209.170 446.640 209.990 ;
        RECT 0.335 207.470 446.640 209.170 ;
        RECT 1.210 206.650 446.640 207.470 ;
        RECT 0.335 204.950 446.640 206.650 ;
        RECT 1.210 204.130 446.640 204.950 ;
        RECT 0.335 202.430 446.640 204.130 ;
        RECT 1.210 201.610 446.640 202.430 ;
        RECT 0.335 199.910 446.640 201.610 ;
        RECT 1.210 199.090 446.640 199.910 ;
        RECT 0.335 197.390 446.640 199.090 ;
        RECT 1.210 196.570 446.640 197.390 ;
        RECT 0.335 194.870 446.640 196.570 ;
        RECT 1.210 194.050 446.640 194.870 ;
        RECT 0.335 192.350 446.640 194.050 ;
        RECT 1.210 191.530 446.640 192.350 ;
        RECT 0.335 189.830 446.640 191.530 ;
        RECT 1.210 189.010 446.640 189.830 ;
        RECT 0.335 187.310 446.640 189.010 ;
        RECT 1.210 186.490 446.640 187.310 ;
        RECT 0.335 184.790 446.640 186.490 ;
        RECT 1.210 183.970 446.640 184.790 ;
        RECT 0.335 182.270 446.640 183.970 ;
        RECT 1.210 181.450 446.640 182.270 ;
        RECT 0.335 179.750 446.640 181.450 ;
        RECT 1.210 178.930 446.640 179.750 ;
        RECT 0.335 177.230 446.640 178.930 ;
        RECT 1.210 176.410 446.640 177.230 ;
        RECT 0.335 174.710 446.640 176.410 ;
        RECT 1.210 173.890 446.640 174.710 ;
        RECT 0.335 172.190 446.640 173.890 ;
        RECT 1.210 171.370 446.640 172.190 ;
        RECT 0.335 169.670 446.640 171.370 ;
        RECT 1.210 168.850 446.640 169.670 ;
        RECT 0.335 167.150 446.640 168.850 ;
        RECT 1.210 166.330 446.640 167.150 ;
        RECT 0.335 164.630 446.640 166.330 ;
        RECT 1.210 163.810 446.640 164.630 ;
        RECT 0.335 162.110 446.640 163.810 ;
        RECT 1.210 161.290 446.640 162.110 ;
        RECT 0.335 159.590 446.640 161.290 ;
        RECT 1.210 158.770 446.640 159.590 ;
        RECT 0.335 157.070 446.640 158.770 ;
        RECT 1.210 156.250 446.640 157.070 ;
        RECT 0.335 154.550 446.640 156.250 ;
        RECT 1.210 153.730 446.640 154.550 ;
        RECT 0.335 152.030 446.640 153.730 ;
        RECT 1.210 151.210 446.640 152.030 ;
        RECT 0.335 149.510 446.640 151.210 ;
        RECT 1.210 148.690 446.640 149.510 ;
        RECT 0.335 146.990 446.640 148.690 ;
        RECT 1.210 146.170 446.640 146.990 ;
        RECT 0.335 144.470 446.640 146.170 ;
        RECT 1.210 143.650 446.640 144.470 ;
        RECT 0.335 141.950 446.640 143.650 ;
        RECT 1.210 141.130 446.640 141.950 ;
        RECT 0.335 139.430 446.640 141.130 ;
        RECT 1.210 138.610 446.640 139.430 ;
        RECT 0.335 136.910 446.640 138.610 ;
        RECT 1.210 136.090 446.640 136.910 ;
        RECT 0.335 134.390 446.640 136.090 ;
        RECT 1.210 133.570 446.640 134.390 ;
        RECT 0.335 131.870 446.640 133.570 ;
        RECT 1.210 131.050 446.640 131.870 ;
        RECT 0.335 129.350 446.640 131.050 ;
        RECT 1.210 128.530 446.640 129.350 ;
        RECT 0.335 126.830 446.640 128.530 ;
        RECT 1.210 126.010 446.640 126.830 ;
        RECT 0.335 124.310 446.640 126.010 ;
        RECT 1.210 123.490 446.640 124.310 ;
        RECT 0.335 121.790 446.640 123.490 ;
        RECT 1.210 120.970 446.640 121.790 ;
        RECT 0.335 119.270 446.640 120.970 ;
        RECT 1.210 118.450 446.640 119.270 ;
        RECT 0.335 116.750 446.640 118.450 ;
        RECT 1.210 115.930 446.640 116.750 ;
        RECT 0.335 114.230 446.640 115.930 ;
        RECT 1.210 113.410 446.640 114.230 ;
        RECT 0.335 111.710 446.640 113.410 ;
        RECT 1.210 110.890 446.640 111.710 ;
        RECT 0.335 109.190 446.640 110.890 ;
        RECT 1.210 108.370 446.640 109.190 ;
        RECT 0.335 106.670 446.640 108.370 ;
        RECT 1.210 105.850 446.640 106.670 ;
        RECT 0.335 104.150 446.640 105.850 ;
        RECT 1.210 103.330 446.640 104.150 ;
        RECT 0.335 101.630 446.640 103.330 ;
        RECT 1.210 100.810 446.640 101.630 ;
        RECT 0.335 99.110 446.640 100.810 ;
        RECT 1.210 98.290 446.640 99.110 ;
        RECT 0.335 96.590 446.640 98.290 ;
        RECT 1.210 95.770 446.640 96.590 ;
        RECT 0.335 94.070 446.640 95.770 ;
        RECT 1.210 93.250 446.640 94.070 ;
        RECT 0.335 91.550 446.640 93.250 ;
        RECT 1.210 90.730 446.640 91.550 ;
        RECT 0.335 89.030 446.640 90.730 ;
        RECT 1.210 88.210 446.640 89.030 ;
        RECT 0.335 86.510 446.640 88.210 ;
        RECT 1.210 85.690 446.640 86.510 ;
        RECT 0.335 83.990 446.640 85.690 ;
        RECT 1.210 83.170 446.640 83.990 ;
        RECT 0.335 81.470 446.640 83.170 ;
        RECT 1.210 80.650 446.640 81.470 ;
        RECT 0.335 78.950 446.640 80.650 ;
        RECT 1.210 78.130 446.640 78.950 ;
        RECT 0.335 76.430 446.640 78.130 ;
        RECT 1.210 75.610 446.640 76.430 ;
        RECT 0.335 73.910 446.640 75.610 ;
        RECT 1.210 73.090 446.640 73.910 ;
        RECT 0.335 71.390 446.640 73.090 ;
        RECT 1.210 70.570 446.640 71.390 ;
        RECT 0.335 68.870 446.640 70.570 ;
        RECT 1.210 68.050 446.640 68.870 ;
        RECT 0.335 66.350 446.640 68.050 ;
        RECT 1.210 65.530 446.640 66.350 ;
        RECT 0.335 63.830 446.640 65.530 ;
        RECT 1.210 63.010 446.640 63.830 ;
        RECT 0.335 61.310 446.640 63.010 ;
        RECT 1.210 60.490 446.640 61.310 ;
        RECT 0.335 58.790 446.640 60.490 ;
        RECT 1.210 57.970 446.640 58.790 ;
        RECT 0.335 56.270 446.640 57.970 ;
        RECT 1.210 55.450 446.640 56.270 ;
        RECT 0.335 53.750 446.640 55.450 ;
        RECT 1.210 52.930 446.640 53.750 ;
        RECT 0.335 51.230 446.640 52.930 ;
        RECT 1.210 50.410 446.640 51.230 ;
        RECT 0.335 48.710 446.640 50.410 ;
        RECT 1.210 47.890 446.640 48.710 ;
        RECT 0.335 46.190 446.640 47.890 ;
        RECT 1.210 45.370 446.640 46.190 ;
        RECT 0.335 43.670 446.640 45.370 ;
        RECT 1.210 42.850 446.640 43.670 ;
        RECT 0.335 41.150 446.640 42.850 ;
        RECT 1.210 40.330 446.640 41.150 ;
        RECT 0.335 38.630 446.640 40.330 ;
        RECT 1.210 37.810 446.640 38.630 ;
        RECT 0.335 36.110 446.640 37.810 ;
        RECT 1.210 35.290 446.640 36.110 ;
        RECT 0.335 33.590 446.640 35.290 ;
        RECT 1.210 32.770 446.640 33.590 ;
        RECT 0.335 31.070 446.640 32.770 ;
        RECT 1.210 30.250 446.640 31.070 ;
        RECT 0.335 28.550 446.640 30.250 ;
        RECT 1.210 27.730 446.640 28.550 ;
        RECT 0.335 26.030 446.640 27.730 ;
        RECT 1.210 25.210 446.640 26.030 ;
        RECT 0.335 23.510 446.640 25.210 ;
        RECT 1.210 22.690 446.640 23.510 ;
        RECT 0.335 20.990 446.640 22.690 ;
        RECT 1.210 20.170 446.640 20.990 ;
        RECT 0.335 18.470 446.640 20.170 ;
        RECT 1.210 17.650 446.640 18.470 ;
        RECT 0.335 15.950 446.640 17.650 ;
        RECT 1.210 15.130 446.640 15.950 ;
        RECT 0.335 11.240 446.640 15.130 ;
      LAYER Metal4 ;
        RECT 0.380 359.530 18.890 481.885 ;
        RECT 0.380 343.550 13.690 359.530 ;
        RECT 15.110 343.550 18.890 359.530 ;
        RECT 0.380 155.410 18.890 343.550 ;
        RECT 0.380 20.000 13.690 155.410 ;
        RECT 15.110 20.000 18.890 155.410 ;
        RECT 20.310 20.000 21.890 481.885 ;
        RECT 23.310 480.810 71.890 481.885 ;
        RECT 73.310 480.810 121.890 481.885 ;
        RECT 123.310 481.050 171.890 481.885 ;
        RECT 173.310 481.050 221.890 481.885 ;
        RECT 223.310 481.050 271.890 481.885 ;
        RECT 273.310 481.050 321.890 481.885 ;
        RECT 323.310 481.050 371.890 481.885 ;
        RECT 373.310 481.050 421.890 481.885 ;
        RECT 423.310 481.050 442.380 481.885 ;
        RECT 123.310 480.810 442.380 481.050 ;
        RECT 23.310 357.970 442.380 480.810 ;
        RECT 23.310 357.730 71.890 357.970 ;
        RECT 23.310 141.050 68.890 357.730 ;
        RECT 70.310 141.050 71.890 357.730 ;
        RECT 23.310 140.810 71.890 141.050 ;
        RECT 73.310 357.730 121.890 357.970 ;
        RECT 73.310 141.050 118.890 357.730 ;
        RECT 120.310 141.050 121.890 357.730 ;
        RECT 73.310 140.810 121.890 141.050 ;
        RECT 123.310 357.730 268.890 357.970 ;
        RECT 123.310 141.050 168.890 357.730 ;
        RECT 170.310 141.050 171.890 357.730 ;
        RECT 173.310 141.050 218.890 357.730 ;
        RECT 220.310 141.050 221.890 357.730 ;
        RECT 223.310 141.050 268.890 357.730 ;
        RECT 123.310 140.810 268.890 141.050 ;
        RECT 270.310 357.730 442.380 357.970 ;
        RECT 270.310 141.050 271.890 357.730 ;
        RECT 273.310 141.050 318.890 357.730 ;
        RECT 320.310 141.050 321.890 357.730 ;
        RECT 323.310 141.050 368.890 357.730 ;
        RECT 370.310 141.050 371.890 357.730 ;
        RECT 373.310 141.050 418.890 357.730 ;
        RECT 420.310 141.050 421.890 357.730 ;
        RECT 423.310 141.050 442.380 357.730 ;
        RECT 270.310 140.810 442.380 141.050 ;
        RECT 23.310 20.000 442.380 140.810 ;
      LAYER TopMetal1 ;
        RECT 10.220 301.060 415.540 330.780 ;
        RECT 10.220 295.060 415.540 295.780 ;
        RECT 10.220 255.030 415.540 289.780 ;
        RECT 10.220 249.030 415.540 249.750 ;
        RECT 10.220 209.000 415.540 243.750 ;
        RECT 10.220 203.000 415.540 203.720 ;
        RECT 10.220 162.970 415.540 197.720 ;
        RECT 10.220 156.970 415.540 157.690 ;
        RECT 10.220 139.900 415.540 151.690 ;
  END
END psum_requant_container
END LIBRARY

